VERSION 5.6 ;
BUSBITCHARS "[]" ;
DIVIDERCHAR "/" ;

## M1-M5 covered, ring power

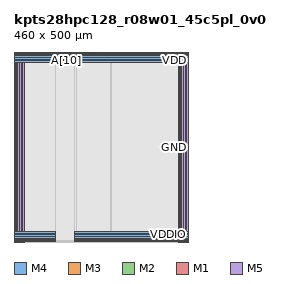
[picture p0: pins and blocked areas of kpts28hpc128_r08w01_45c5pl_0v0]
MACRO kpts28hpc128_r08w01_45c5pl_0v0
  CLASS RING ;
  ORIGIN 0 0 ;
  FOREIGN kpts28hpc128_r08w01_45c5pl_0v0 0 0 ;
  SIZE 460 BY 500 ;
  SYMMETRY X Y ;
  PIN A[0]
    DIRECTION INPUT ;
    USE SIGNAL ;
    ANTENNAPARTIALMETALAREA 0.21865 LAYER M3 ;
    ANTENNAPARTIALMETALAREA 0.0143 LAYER M2 ;
    ANTENNAPARTIALMETALAREA 0.0143 LAYER M4 ;
    ANTENNAPARTIALMETALAREA 0.0143 LAYER M1 ;
    ANTENNAPARTIALCUTAREA 0.005 LAYER VIA3 ;
    ANTENNAPARTIALCUTAREA 0.005 LAYER VIA2 ;
    ANTENNAPARTIALCUTAREA 0.005 LAYER VIA1 ;
    ANTENNAMODEL OXIDE1 ;
      ANTENNAGATEAREA 0.0217 LAYER M3 ;
      ANTENNAGATEAREA 0.0217 LAYER M4 ;
      ANTENNAMAXAREACAR 12.52765 LAYER M3 ;
      ANTENNAMAXAREACAR 13.74424 LAYER M4 ;
      ANTENNAMAXSIDEAREACAR 24.345622 LAYER M3 ;
      ANTENNAMAXSIDEAREACAR 27.248848 LAYER M4 ;
      ANTENNAMAXCUTCAR 0.691244 LAYER VIA3 ;
    PORT
      LAYER M4 ;
        RECT 153.79 499.89 153.9 500 ;
      LAYER M3 ;
        RECT 153.79 499.89 153.9 500 ;
      LAYER M2 ;
        RECT 153.79 499.89 153.9 500 ;
      LAYER M1 ;
        RECT 153.79 499.89 153.9 500 ;
    END
  END A[0]
  PIN A[10]
    DIRECTION INPUT ;
    USE SIGNAL ;
    ANTENNAPARTIALMETALAREA 0.21865 LAYER M3 ;
    ANTENNAPARTIALMETALAREA 0.0143 LAYER M2 ;
    ANTENNAPARTIALMETALAREA 0.0143 LAYER M4 ;
    ANTENNAPARTIALMETALAREA 0.0143 LAYER M1 ;
    ANTENNAPARTIALCUTAREA 0.005 LAYER VIA3 ;
    ANTENNAPARTIALCUTAREA 0.005 LAYER VIA2 ;
    ANTENNAPARTIALCUTAREA 0.005 LAYER VIA1 ;
    ANTENNAMODEL OXIDE1 ;
      ANTENNAGATEAREA 0.0217 LAYER M3 ;
      ANTENNAGATEAREA 0.0217 LAYER M4 ;
      ANTENNAMAXAREACAR 12.52765 LAYER M3 ;
      ANTENNAMAXAREACAR 13.74424 LAYER M4 ;
      ANTENNAMAXSIDEAREACAR 24.345622 LAYER M3 ;
      ANTENNAMAXSIDEAREACAR 27.248848 LAYER M4 ;
      ANTENNAMAXCUTCAR 0.691244 LAYER VIA3 ;
    PORT
      LAYER M4 ;
        RECT 137.59 499.89 137.7 500 ;
      LAYER M3 ;
        RECT 137.59 499.89 137.7 500 ;
      LAYER M2 ;
        RECT 137.59 499.89 137.7 500 ;
      LAYER M1 ;
        RECT 137.59 499.89 137.7 500 ;
    END
  END A[10]
  PIN A[11]
    DIRECTION INPUT ;
    USE SIGNAL ;
    ANTENNAPARTIALMETALAREA 0.21865 LAYER M3 ;
    ANTENNAPARTIALMETALAREA 0.0143 LAYER M2 ;
    ANTENNAPARTIALMETALAREA 0.0143 LAYER M4 ;
    ANTENNAPARTIALMETALAREA 0.0143 LAYER M1 ;
    ANTENNAPARTIALCUTAREA 0.005 LAYER VIA3 ;
    ANTENNAPARTIALCUTAREA 0.005 LAYER VIA2 ;
    ANTENNAPARTIALCUTAREA 0.005 LAYER VIA1 ;
    ANTENNAMODEL OXIDE1 ;
      ANTENNAGATEAREA 0.0217 LAYER M3 ;
      ANTENNAGATEAREA 0.0217 LAYER M4 ;
      ANTENNAMAXAREACAR 12.52765 LAYER M3 ;
      ANTENNAMAXAREACAR 13.74424 LAYER M4 ;
      ANTENNAMAXSIDEAREACAR 24.345622 LAYER M3 ;
      ANTENNAMAXSIDEAREACAR 27.248848 LAYER M4 ;
      ANTENNAMAXCUTCAR 0.691244 LAYER VIA3 ;
    PORT
      LAYER M4 ;
        RECT 135.97 499.89 136.08 500 ;
      LAYER M3 ;
        RECT 135.97 499.89 136.08 500 ;
      LAYER M2 ;
        RECT 135.97 499.89 136.08 500 ;
      LAYER M1 ;
        RECT 135.97 499.89 136.08 500 ;
    END
  END A[11]
  PIN A[12]
    DIRECTION INPUT ;
    USE SIGNAL ;
    ANTENNAPARTIALMETALAREA 0.21865 LAYER M3 ;
    ANTENNAPARTIALMETALAREA 0.0143 LAYER M2 ;
    ANTENNAPARTIALMETALAREA 0.0143 LAYER M4 ;
    ANTENNAPARTIALMETALAREA 0.0143 LAYER M1 ;
    ANTENNAPARTIALCUTAREA 0.005 LAYER VIA3 ;
    ANTENNAPARTIALCUTAREA 0.005 LAYER VIA2 ;
    ANTENNAPARTIALCUTAREA 0.005 LAYER VIA1 ;
    ANTENNAMODEL OXIDE1 ;
      ANTENNAGATEAREA 0.0217 LAYER M3 ;
      ANTENNAGATEAREA 0.0217 LAYER M4 ;
      ANTENNAMAXAREACAR 12.52765 LAYER M3 ;
      ANTENNAMAXAREACAR 13.74424 LAYER M4 ;
      ANTENNAMAXSIDEAREACAR 24.345622 LAYER M3 ;
      ANTENNAMAXSIDEAREACAR 27.248848 LAYER M4 ;
      ANTENNAMAXCUTCAR 0.691244 LAYER VIA3 ;
    PORT
      LAYER M4 ;
        RECT 134.35 499.89 134.46 500 ;
      LAYER M3 ;
        RECT 134.35 499.89 134.46 500 ;
      LAYER M2 ;
        RECT 134.35 499.89 134.46 500 ;
      LAYER M1 ;
        RECT 134.35 499.89 134.46 500 ;
    END
  END A[12]
  PIN A[13]
    DIRECTION INPUT ;
    USE SIGNAL ;
    ANTENNAPARTIALMETALAREA 0.21865 LAYER M3 ;
    ANTENNAPARTIALMETALAREA 0.0143 LAYER M2 ;
    ANTENNAPARTIALMETALAREA 0.0143 LAYER M4 ;
    ANTENNAPARTIALMETALAREA 0.0143 LAYER M1 ;
    ANTENNAPARTIALCUTAREA 0.005 LAYER VIA3 ;
    ANTENNAPARTIALCUTAREA 0.005 LAYER VIA2 ;
    ANTENNAPARTIALCUTAREA 0.005 LAYER VIA1 ;
    ANTENNAMODEL OXIDE1 ;
      ANTENNAGATEAREA 0.0217 LAYER M3 ;
      ANTENNAGATEAREA 0.0217 LAYER M4 ;
      ANTENNAMAXAREACAR 12.52765 LAYER M3 ;
      ANTENNAMAXAREACAR 13.74424 LAYER M4 ;
      ANTENNAMAXSIDEAREACAR 24.345622 LAYER M3 ;
      ANTENNAMAXSIDEAREACAR 27.248848 LAYER M4 ;
      ANTENNAMAXCUTCAR 0.691244 LAYER VIA3 ;
    PORT
      LAYER M4 ;
        RECT 132.73 499.89 132.84 500 ;
      LAYER M3 ;
        RECT 132.73 499.89 132.84 500 ;
      LAYER M2 ;
        RECT 132.73 499.89 132.84 500 ;
      LAYER M1 ;
        RECT 132.73 499.89 132.84 500 ;
    END
  END A[13]
  PIN A[14]
    DIRECTION INPUT ;
    USE SIGNAL ;
    ANTENNAPARTIALMETALAREA 0.21865 LAYER M3 ;
    ANTENNAPARTIALMETALAREA 0.0143 LAYER M2 ;
    ANTENNAPARTIALMETALAREA 0.0143 LAYER M4 ;
    ANTENNAPARTIALMETALAREA 0.0143 LAYER M1 ;
    ANTENNAPARTIALCUTAREA 0.005 LAYER VIA3 ;
    ANTENNAPARTIALCUTAREA 0.005 LAYER VIA2 ;
    ANTENNAPARTIALCUTAREA 0.005 LAYER VIA1 ;
    ANTENNAMODEL OXIDE1 ;
      ANTENNAGATEAREA 0.0217 LAYER M3 ;
      ANTENNAGATEAREA 0.0217 LAYER M4 ;
      ANTENNAMAXAREACAR 12.52765 LAYER M3 ;
      ANTENNAMAXAREACAR 13.74424 LAYER M4 ;
      ANTENNAMAXSIDEAREACAR 24.345622 LAYER M3 ;
      ANTENNAMAXSIDEAREACAR 27.248848 LAYER M4 ;
      ANTENNAMAXCUTCAR 0.691244 LAYER VIA3 ;
    PORT
      LAYER M4 ;
        RECT 131.11 499.89 131.22 500 ;
      LAYER M3 ;
        RECT 131.11 499.89 131.22 500 ;
      LAYER M2 ;
        RECT 131.11 499.89 131.22 500 ;
      LAYER M1 ;
        RECT 131.11 499.89 131.22 500 ;
    END
  END A[14]
  PIN A[15]
    DIRECTION INPUT ;
    USE SIGNAL ;
    ANTENNAPARTIALMETALAREA 0.21865 LAYER M3 ;
    ANTENNAPARTIALMETALAREA 0.0143 LAYER M2 ;
    ANTENNAPARTIALMETALAREA 0.0143 LAYER M4 ;
    ANTENNAPARTIALMETALAREA 0.0143 LAYER M1 ;
    ANTENNAPARTIALCUTAREA 0.005 LAYER VIA3 ;
    ANTENNAPARTIALCUTAREA 0.005 LAYER VIA2 ;
    ANTENNAPARTIALCUTAREA 0.005 LAYER VIA1 ;
    ANTENNAMODEL OXIDE1 ;
      ANTENNAGATEAREA 0.0217 LAYER M3 ;
      ANTENNAGATEAREA 0.0217 LAYER M4 ;
      ANTENNAMAXAREACAR 12.52765 LAYER M3 ;
      ANTENNAMAXAREACAR 13.74424 LAYER M4 ;
      ANTENNAMAXSIDEAREACAR 24.345622 LAYER M3 ;
      ANTENNAMAXSIDEAREACAR 27.248848 LAYER M4 ;
      ANTENNAMAXCUTCAR 0.691244 LAYER VIA3 ;
    PORT
      LAYER M4 ;
        RECT 129.49 499.89 129.6 500 ;
      LAYER M3 ;
        RECT 129.49 499.89 129.6 500 ;
      LAYER M2 ;
        RECT 129.49 499.89 129.6 500 ;
      LAYER M1 ;
        RECT 129.49 499.89 129.6 500 ;
    END
  END A[15]
  PIN A[16]
    DIRECTION INPUT ;
    USE SIGNAL ;
    ANTENNAPARTIALMETALAREA 0.21865 LAYER M3 ;
    ANTENNAPARTIALMETALAREA 0.0143 LAYER M2 ;
    ANTENNAPARTIALMETALAREA 0.0143 LAYER M4 ;
    ANTENNAPARTIALMETALAREA 0.0143 LAYER M1 ;
    ANTENNAPARTIALCUTAREA 0.005 LAYER VIA3 ;
    ANTENNAPARTIALCUTAREA 0.005 LAYER VIA2 ;
    ANTENNAPARTIALCUTAREA 0.005 LAYER VIA1 ;
    ANTENNAMODEL OXIDE1 ;
      ANTENNAGATEAREA 0.0217 LAYER M3 ;
      ANTENNAGATEAREA 0.0217 LAYER M4 ;
      ANTENNAMAXAREACAR 12.52765 LAYER M3 ;
      ANTENNAMAXAREACAR 13.74424 LAYER M4 ;
      ANTENNAMAXSIDEAREACAR 24.345622 LAYER M3 ;
      ANTENNAMAXSIDEAREACAR 27.248848 LAYER M4 ;
      ANTENNAMAXCUTCAR 0.691244 LAYER VIA3 ;
    PORT
      LAYER M4 ;
        RECT 127.87 499.89 127.98 500 ;
      LAYER M3 ;
        RECT 127.87 499.89 127.98 500 ;
      LAYER M2 ;
        RECT 127.87 499.89 127.98 500 ;
      LAYER M1 ;
        RECT 127.87 499.89 127.98 500 ;
    END
  END A[16]
  PIN A[1]
    DIRECTION INPUT ;
    USE SIGNAL ;
    ANTENNAPARTIALMETALAREA 0.21865 LAYER M3 ;
    ANTENNAPARTIALMETALAREA 0.0143 LAYER M2 ;
    ANTENNAPARTIALMETALAREA 0.0143 LAYER M4 ;
    ANTENNAPARTIALMETALAREA 0.0143 LAYER M1 ;
    ANTENNAPARTIALCUTAREA 0.005 LAYER VIA3 ;
    ANTENNAPARTIALCUTAREA 0.005 LAYER VIA2 ;
    ANTENNAPARTIALCUTAREA 0.005 LAYER VIA1 ;
    ANTENNAMODEL OXIDE1 ;
      ANTENNAGATEAREA 0.0217 LAYER M3 ;
      ANTENNAGATEAREA 0.0217 LAYER M4 ;
      ANTENNAMAXAREACAR 12.52765 LAYER M3 ;
      ANTENNAMAXAREACAR 13.74424 LAYER M4 ;
      ANTENNAMAXSIDEAREACAR 24.345622 LAYER M3 ;
      ANTENNAMAXSIDEAREACAR 27.248848 LAYER M4 ;
      ANTENNAMAXCUTCAR 0.691244 LAYER VIA3 ;
    PORT
      LAYER M4 ;
        RECT 152.17 499.89 152.28 500 ;
      LAYER M3 ;
        RECT 152.17 499.89 152.28 500 ;
      LAYER M2 ;
        RECT 152.17 499.89 152.28 500 ;
      LAYER M1 ;
        RECT 152.17 499.89 152.28 500 ;
    END
  END A[1]
  PIN A[2]
    DIRECTION INPUT ;
    USE SIGNAL ;
    ANTENNAPARTIALMETALAREA 0.21865 LAYER M3 ;
    ANTENNAPARTIALMETALAREA 0.0143 LAYER M2 ;
    ANTENNAPARTIALMETALAREA 0.0143 LAYER M4 ;
    ANTENNAPARTIALMETALAREA 0.0143 LAYER M1 ;
    ANTENNAPARTIALCUTAREA 0.005 LAYER VIA3 ;
    ANTENNAPARTIALCUTAREA 0.005 LAYER VIA2 ;
    ANTENNAPARTIALCUTAREA 0.005 LAYER VIA1 ;
    ANTENNAMODEL OXIDE1 ;
      ANTENNAGATEAREA 0.0217 LAYER M3 ;
      ANTENNAGATEAREA 0.0217 LAYER M4 ;
      ANTENNAMAXAREACAR 12.52765 LAYER M3 ;
      ANTENNAMAXAREACAR 13.74424 LAYER M4 ;
      ANTENNAMAXSIDEAREACAR 24.345622 LAYER M3 ;
      ANTENNAMAXSIDEAREACAR 27.248848 LAYER M4 ;
      ANTENNAMAXCUTCAR 0.691244 LAYER VIA3 ;
    PORT
      LAYER M4 ;
        RECT 150.55 499.89 150.66 500 ;
      LAYER M3 ;
        RECT 150.55 499.89 150.66 500 ;
      LAYER M2 ;
        RECT 150.55 499.89 150.66 500 ;
      LAYER M1 ;
        RECT 150.55 499.89 150.66 500 ;
    END
  END A[2]
  PIN A[3]
    DIRECTION INPUT ;
    USE SIGNAL ;
    ANTENNAPARTIALMETALAREA 0.21865 LAYER M3 ;
    ANTENNAPARTIALMETALAREA 0.0143 LAYER M2 ;
    ANTENNAPARTIALMETALAREA 0.0143 LAYER M4 ;
    ANTENNAPARTIALMETALAREA 0.0143 LAYER M1 ;
    ANTENNAPARTIALCUTAREA 0.005 LAYER VIA3 ;
    ANTENNAPARTIALCUTAREA 0.005 LAYER VIA2 ;
    ANTENNAPARTIALCUTAREA 0.005 LAYER VIA1 ;
    ANTENNAMODEL OXIDE1 ;
      ANTENNAGATEAREA 0.0217 LAYER M3 ;
      ANTENNAGATEAREA 0.0217 LAYER M4 ;
      ANTENNAMAXAREACAR 12.52765 LAYER M3 ;
      ANTENNAMAXAREACAR 13.74424 LAYER M4 ;
      ANTENNAMAXSIDEAREACAR 24.345622 LAYER M3 ;
      ANTENNAMAXSIDEAREACAR 27.248848 LAYER M4 ;
      ANTENNAMAXCUTCAR 0.691244 LAYER VIA3 ;
    PORT
      LAYER M4 ;
        RECT 148.93 499.89 149.04 500 ;
      LAYER M3 ;
        RECT 148.93 499.89 149.04 500 ;
      LAYER M2 ;
        RECT 148.93 499.89 149.04 500 ;
      LAYER M1 ;
        RECT 148.93 499.89 149.04 500 ;
    END
  END A[3]
  PIN A[4]
    DIRECTION INPUT ;
    USE SIGNAL ;
    ANTENNAPARTIALMETALAREA 0.21865 LAYER M3 ;
    ANTENNAPARTIALMETALAREA 0.0143 LAYER M2 ;
    ANTENNAPARTIALMETALAREA 0.0143 LAYER M4 ;
    ANTENNAPARTIALMETALAREA 0.0143 LAYER M1 ;
    ANTENNAPARTIALCUTAREA 0.005 LAYER VIA3 ;
    ANTENNAPARTIALCUTAREA 0.005 LAYER VIA2 ;
    ANTENNAPARTIALCUTAREA 0.005 LAYER VIA1 ;
    ANTENNAMODEL OXIDE1 ;
      ANTENNAGATEAREA 0.0217 LAYER M3 ;
      ANTENNAGATEAREA 0.0217 LAYER M4 ;
      ANTENNAMAXAREACAR 12.52765 LAYER M3 ;
      ANTENNAMAXAREACAR 13.74424 LAYER M4 ;
      ANTENNAMAXSIDEAREACAR 24.345622 LAYER M3 ;
      ANTENNAMAXSIDEAREACAR 27.248848 LAYER M4 ;
      ANTENNAMAXCUTCAR 0.691244 LAYER VIA3 ;
    PORT
      LAYER M4 ;
        RECT 147.31 499.89 147.42 500 ;
      LAYER M3 ;
        RECT 147.31 499.89 147.42 500 ;
      LAYER M2 ;
        RECT 147.31 499.89 147.42 500 ;
      LAYER M1 ;
        RECT 147.31 499.89 147.42 500 ;
    END
  END A[4]
  PIN A[5]
    DIRECTION INPUT ;
    USE SIGNAL ;
    ANTENNAPARTIALMETALAREA 0.21865 LAYER M3 ;
    ANTENNAPARTIALMETALAREA 0.0143 LAYER M2 ;
    ANTENNAPARTIALMETALAREA 0.0143 LAYER M4 ;
    ANTENNAPARTIALMETALAREA 0.0143 LAYER M1 ;
    ANTENNAPARTIALCUTAREA 0.005 LAYER VIA3 ;
    ANTENNAPARTIALCUTAREA 0.005 LAYER VIA2 ;
    ANTENNAPARTIALCUTAREA 0.005 LAYER VIA1 ;
    ANTENNAMODEL OXIDE1 ;
      ANTENNAGATEAREA 0.0217 LAYER M3 ;
      ANTENNAGATEAREA 0.0217 LAYER M4 ;
      ANTENNAMAXAREACAR 12.52765 LAYER M3 ;
      ANTENNAMAXAREACAR 13.74424 LAYER M4 ;
      ANTENNAMAXSIDEAREACAR 24.345622 LAYER M3 ;
      ANTENNAMAXSIDEAREACAR 27.248848 LAYER M4 ;
      ANTENNAMAXCUTCAR 0.691244 LAYER VIA3 ;
    PORT
      LAYER M4 ;
        RECT 145.69 499.89 145.8 500 ;
      LAYER M3 ;
        RECT 145.69 499.89 145.8 500 ;
      LAYER M2 ;
        RECT 145.69 499.89 145.8 500 ;
      LAYER M1 ;
        RECT 145.69 499.89 145.8 500 ;
    END
  END A[5]
  PIN A[6]
    DIRECTION INPUT ;
    USE SIGNAL ;
    ANTENNAPARTIALMETALAREA 0.21865 LAYER M3 ;
    ANTENNAPARTIALMETALAREA 0.0143 LAYER M2 ;
    ANTENNAPARTIALMETALAREA 0.0143 LAYER M4 ;
    ANTENNAPARTIALMETALAREA 0.0143 LAYER M1 ;
    ANTENNAPARTIALCUTAREA 0.005 LAYER VIA3 ;
    ANTENNAPARTIALCUTAREA 0.005 LAYER VIA2 ;
    ANTENNAPARTIALCUTAREA 0.005 LAYER VIA1 ;
    ANTENNAMODEL OXIDE1 ;
      ANTENNAGATEAREA 0.0217 LAYER M3 ;
      ANTENNAGATEAREA 0.0217 LAYER M4 ;
      ANTENNAMAXAREACAR 12.52765 LAYER M3 ;
      ANTENNAMAXAREACAR 13.74424 LAYER M4 ;
      ANTENNAMAXSIDEAREACAR 24.345622 LAYER M3 ;
      ANTENNAMAXSIDEAREACAR 27.248848 LAYER M4 ;
      ANTENNAMAXCUTCAR 0.691244 LAYER VIA3 ;
    PORT
      LAYER M4 ;
        RECT 144.07 499.89 144.18 500 ;
      LAYER M3 ;
        RECT 144.07 499.89 144.18 500 ;
      LAYER M2 ;
        RECT 144.07 499.89 144.18 500 ;
      LAYER M1 ;
        RECT 144.07 499.89 144.18 500 ;
    END
  END A[6]
  PIN A[7]
    DIRECTION INPUT ;
    USE SIGNAL ;
    ANTENNAPARTIALMETALAREA 0.21865 LAYER M3 ;
    ANTENNAPARTIALMETALAREA 0.0143 LAYER M2 ;
    ANTENNAPARTIALMETALAREA 0.0143 LAYER M4 ;
    ANTENNAPARTIALMETALAREA 0.0143 LAYER M1 ;
    ANTENNAPARTIALCUTAREA 0.005 LAYER VIA3 ;
    ANTENNAPARTIALCUTAREA 0.005 LAYER VIA2 ;
    ANTENNAPARTIALCUTAREA 0.005 LAYER VIA1 ;
    ANTENNAMODEL OXIDE1 ;
      ANTENNAGATEAREA 0.0217 LAYER M3 ;
      ANTENNAGATEAREA 0.0217 LAYER M4 ;
      ANTENNAMAXAREACAR 12.52765 LAYER M3 ;
      ANTENNAMAXAREACAR 13.74424 LAYER M4 ;
      ANTENNAMAXSIDEAREACAR 24.345622 LAYER M3 ;
      ANTENNAMAXSIDEAREACAR 27.248848 LAYER M4 ;
      ANTENNAMAXCUTCAR 0.691244 LAYER VIA3 ;
    PORT
      LAYER M4 ;
        RECT 142.45 499.89 142.56 500 ;
      LAYER M3 ;
        RECT 142.45 499.89 142.56 500 ;
      LAYER M2 ;
        RECT 142.45 499.89 142.56 500 ;
      LAYER M1 ;
        RECT 142.45 499.89 142.56 500 ;
    END
  END A[7]
  PIN A[8]
    DIRECTION INPUT ;
    USE SIGNAL ;
    ANTENNAPARTIALMETALAREA 0.21865 LAYER M3 ;
    ANTENNAPARTIALMETALAREA 0.0143 LAYER M2 ;
    ANTENNAPARTIALMETALAREA 0.0143 LAYER M4 ;
    ANTENNAPARTIALMETALAREA 0.0143 LAYER M1 ;
    ANTENNAPARTIALCUTAREA 0.005 LAYER VIA3 ;
    ANTENNAPARTIALCUTAREA 0.005 LAYER VIA2 ;
    ANTENNAPARTIALCUTAREA 0.005 LAYER VIA1 ;
    ANTENNAMODEL OXIDE1 ;
      ANTENNAGATEAREA 0.0217 LAYER M3 ;
      ANTENNAGATEAREA 0.0217 LAYER M4 ;
      ANTENNAMAXAREACAR 12.52765 LAYER M3 ;
      ANTENNAMAXAREACAR 13.74424 LAYER M4 ;
      ANTENNAMAXSIDEAREACAR 24.345622 LAYER M3 ;
      ANTENNAMAXSIDEAREACAR 27.248848 LAYER M4 ;
      ANTENNAMAXCUTCAR 0.691244 LAYER VIA3 ;
    PORT
      LAYER M4 ;
        RECT 140.83 499.89 140.94 500 ;
      LAYER M3 ;
        RECT 140.83 499.89 140.94 500 ;
      LAYER M2 ;
        RECT 140.83 499.89 140.94 500 ;
      LAYER M1 ;
        RECT 140.83 499.89 140.94 500 ;
    END
  END A[8]
  PIN A[9]
    DIRECTION INPUT ;
    USE SIGNAL ;
    ANTENNAPARTIALMETALAREA 0.21865 LAYER M3 ;
    ANTENNAPARTIALMETALAREA 0.0143 LAYER M2 ;
    ANTENNAPARTIALMETALAREA 0.0143 LAYER M4 ;
    ANTENNAPARTIALMETALAREA 0.0143 LAYER M1 ;
    ANTENNAPARTIALCUTAREA 0.005 LAYER VIA3 ;
    ANTENNAPARTIALCUTAREA 0.005 LAYER VIA2 ;
    ANTENNAPARTIALCUTAREA 0.005 LAYER VIA1 ;
    ANTENNAMODEL OXIDE1 ;
      ANTENNAGATEAREA 0.0217 LAYER M3 ;
      ANTENNAGATEAREA 0.0217 LAYER M4 ;
      ANTENNAMAXAREACAR 12.52765 LAYER M3 ;
      ANTENNAMAXAREACAR 13.74424 LAYER M4 ;
      ANTENNAMAXSIDEAREACAR 24.345622 LAYER M3 ;
      ANTENNAMAXSIDEAREACAR 27.248848 LAYER M4 ;
      ANTENNAMAXCUTCAR 0.691244 LAYER VIA3 ;
    PORT
      LAYER M4 ;
        RECT 139.21 499.89 139.32 500 ;
      LAYER M3 ;
        RECT 139.21 499.89 139.32 500 ;
      LAYER M2 ;
        RECT 139.21 499.89 139.32 500 ;
      LAYER M1 ;
        RECT 139.21 499.89 139.32 500 ;
    END
  END A[9]
  PIN CEB
    DIRECTION INPUT ;
    USE SIGNAL ;
    ANTENNAPARTIALMETALAREA 0.20325 LAYER M3 ;
    ANTENNAPARTIALMETALAREA 0.0143 LAYER M2 ;
    ANTENNAPARTIALMETALAREA 0.0143 LAYER M4 ;
    ANTENNAPARTIALMETALAREA 0.0143 LAYER M1 ;
    ANTENNAPARTIALCUTAREA 0.005 LAYER VIA3 ;
    ANTENNAPARTIALCUTAREA 0.005 LAYER VIA2 ;
    ANTENNAPARTIALCUTAREA 0.005 LAYER VIA1 ;
    ANTENNAMODEL OXIDE1 ;
      ANTENNAGATEAREA 0.0217 LAYER M3 ;
      ANTENNAGATEAREA 0.0217 LAYER M4 ;
      ANTENNAMAXAREACAR 10.914747 LAYER M3 ;
      ANTENNAMAXAREACAR 12.131336 LAYER M4 ;
      ANTENNAMAXSIDEAREACAR 20.861751 LAYER M3 ;
      ANTENNAMAXSIDEAREACAR 23.764977 LAYER M4 ;
      ANTENNAMAXCUTCAR 0.691244 LAYER VIA3 ;
    PORT
      LAYER M4 ;
        RECT 155.325 499.89 155.435 500 ;
      LAYER M3 ;
        RECT 155.325 499.89 155.435 500 ;
      LAYER M2 ;
        RECT 155.325 499.89 155.435 500 ;
      LAYER M1 ;
        RECT 155.325 499.89 155.435 500 ;
    END
  END CEB
  PIN CLE
    DIRECTION INPUT ;
    USE SIGNAL ;
    ANTENNAPARTIALMETALAREA 0.21865 LAYER M3 ;
    ANTENNAPARTIALMETALAREA 0.0143 LAYER M2 ;
    ANTENNAPARTIALMETALAREA 0.0143 LAYER M4 ;
    ANTENNAPARTIALMETALAREA 0.0143 LAYER M1 ;
    ANTENNAPARTIALCUTAREA 0.005 LAYER VIA3 ;
    ANTENNAPARTIALCUTAREA 0.005 LAYER VIA2 ;
    ANTENNAPARTIALCUTAREA 0.005 LAYER VIA1 ;
    ANTENNAMODEL OXIDE1 ;
      ANTENNAGATEAREA 0.0217 LAYER M3 ;
      ANTENNAGATEAREA 0.0217 LAYER M4 ;
      ANTENNAMAXAREACAR 12.52765 LAYER M3 ;
      ANTENNAMAXAREACAR 13.74424 LAYER M4 ;
      ANTENNAMAXSIDEAREACAR 24.345622 LAYER M3 ;
      ANTENNAMAXSIDEAREACAR 27.248848 LAYER M4 ;
      ANTENNAMAXCUTCAR 0.691244 LAYER VIA3 ;
    PORT
      LAYER M4 ;
        RECT 113.965 499.89 114.075 500 ;
      LAYER M3 ;
        RECT 113.965 499.89 114.075 500 ;
      LAYER M2 ;
        RECT 113.965 499.89 114.075 500 ;
      LAYER M1 ;
        RECT 113.965 499.89 114.075 500 ;
    END
  END CLE
  PIN CPUMPEN
    DIRECTION INPUT ;
    USE SIGNAL ;
    ANTENNAPARTIALMETALAREA 0.21865 LAYER M3 ;
    ANTENNAPARTIALMETALAREA 0.0143 LAYER M2 ;
    ANTENNAPARTIALMETALAREA 0.0143 LAYER M4 ;
    ANTENNAPARTIALMETALAREA 0.0143 LAYER M1 ;
    ANTENNAPARTIALCUTAREA 0.005 LAYER VIA3 ;
    ANTENNAPARTIALCUTAREA 0.005 LAYER VIA2 ;
    ANTENNAPARTIALCUTAREA 0.005 LAYER VIA1 ;
    ANTENNAMODEL OXIDE1 ;
      ANTENNAGATEAREA 0.0217 LAYER M3 ;
      ANTENNAGATEAREA 0.0217 LAYER M4 ;
      ANTENNAMAXAREACAR 12.52765 LAYER M3 ;
      ANTENNAMAXAREACAR 13.74424 LAYER M4 ;
      ANTENNAMAXSIDEAREACAR 24.345622 LAYER M3 ;
      ANTENNAMAXSIDEAREACAR 27.248848 LAYER M4 ;
      ANTENNAMAXCUTCAR 0.691244 LAYER VIA3 ;
    PORT
      LAYER M4 ;
        RECT 116.665 499.89 116.775 500 ;
      LAYER M3 ;
        RECT 116.665 499.89 116.775 500 ;
      LAYER M2 ;
        RECT 116.665 499.89 116.775 500 ;
      LAYER M1 ;
        RECT 116.665 499.89 116.775 500 ;
    END
  END CPUMPEN
  PIN DIN
    DIRECTION INPUT ;
    USE SIGNAL ;
    ANTENNAPARTIALMETALAREA 0.20955 LAYER M3 ;
    ANTENNAPARTIALMETALAREA 0.0143 LAYER M2 ;
    ANTENNAPARTIALMETALAREA 0.0143 LAYER M4 ;
    ANTENNAPARTIALMETALAREA 0.0143 LAYER M1 ;
    ANTENNAPARTIALCUTAREA 0.005 LAYER VIA3 ;
    ANTENNAPARTIALCUTAREA 0.005 LAYER VIA2 ;
    ANTENNAPARTIALCUTAREA 0.005 LAYER VIA1 ;
    ANTENNAMODEL OXIDE1 ;
      ANTENNAGATEAREA 0.0217 LAYER M3 ;
      ANTENNAGATEAREA 0.0217 LAYER M4 ;
      ANTENNAMAXAREACAR 11.085253 LAYER M3 ;
      ANTENNAMAXAREACAR 12.301843 LAYER M4 ;
      ANTENNAMAXSIDEAREACAR 21.774194 LAYER M3 ;
      ANTENNAMAXSIDEAREACAR 24.677419 LAYER M4 ;
      ANTENNAMAXCUTCAR 0.691244 LAYER VIA3 ;
    PORT
      LAYER M4 ;
        RECT 161.965 499.89 162.075 500 ;
      LAYER M3 ;
        RECT 161.965 499.89 162.075 500 ;
      LAYER M2 ;
        RECT 161.965 499.89 162.075 500 ;
      LAYER M1 ;
        RECT 161.965 499.89 162.075 500 ;
    END
  END DIN
  PIN DLE
    DIRECTION INPUT ;
    USE SIGNAL ;
    ANTENNAPARTIALMETALAREA 0.21865 LAYER M3 ;
    ANTENNAPARTIALMETALAREA 0.0143 LAYER M2 ;
    ANTENNAPARTIALMETALAREA 0.0143 LAYER M4 ;
    ANTENNAPARTIALMETALAREA 0.0143 LAYER M1 ;
    ANTENNAPARTIALCUTAREA 0.005 LAYER VIA3 ;
    ANTENNAPARTIALCUTAREA 0.005 LAYER VIA2 ;
    ANTENNAPARTIALCUTAREA 0.005 LAYER VIA1 ;
    ANTENNAMODEL OXIDE1 ;
      ANTENNAGATEAREA 0.0217 LAYER M3 ;
      ANTENNAGATEAREA 0.0217 LAYER M4 ;
      ANTENNAMAXAREACAR 12.52765 LAYER M3 ;
      ANTENNAMAXAREACAR 13.74424 LAYER M4 ;
      ANTENNAMAXSIDEAREACAR 24.345622 LAYER M3 ;
      ANTENNAMAXSIDEAREACAR 27.248848 LAYER M4 ;
      ANTENNAMAXCUTCAR 0.691244 LAYER VIA3 ;
    PORT
      LAYER M4 ;
        RECT 115.315 499.89 115.425 500 ;
      LAYER M3 ;
        RECT 115.315 499.89 115.425 500 ;
      LAYER M2 ;
        RECT 115.315 499.89 115.425 500 ;
      LAYER M1 ;
        RECT 115.315 499.89 115.425 500 ;
    END
  END DLE
  PIN D[0]
    DIRECTION OUTPUT ;
    USE SIGNAL ;
    ANTENNAPARTIALMETALAREA 9.196 LAYER M3 ;
    ANTENNAPARTIALMETALAREA 0.0143 LAYER M2 ;
    ANTENNAPARTIALMETALAREA 2.9073 LAYER M4 ;
    ANTENNAPARTIALMETALAREA 0.0143 LAYER M1 ;
    ANTENNAPARTIALCUTAREA 0.01 LAYER VIA3 ;
    ANTENNAPARTIALCUTAREA 0.005 LAYER VIA2 ;
    ANTENNAPARTIALCUTAREA 0.005 LAYER VIA1 ;
    PORT
      LAYER M4 ;
        RECT 170.445 499.89 170.555 500 ;
      LAYER M3 ;
        RECT 170.445 499.89 170.555 500 ;
      LAYER M2 ;
        RECT 170.445 499.89 170.555 500 ;
      LAYER M1 ;
        RECT 170.445 499.89 170.555 500 ;
    END
  END D[0]
  PIN D[1]
    DIRECTION OUTPUT ;
    USE SIGNAL ;
    ANTENNAPARTIALMETALAREA 9.2202 LAYER M3 ;
    ANTENNAPARTIALMETALAREA 0.0143 LAYER M2 ;
    ANTENNAPARTIALMETALAREA 2.9073 LAYER M4 ;
    ANTENNAPARTIALMETALAREA 0.0143 LAYER M1 ;
    ANTENNAPARTIALCUTAREA 0.01 LAYER VIA3 ;
    ANTENNAPARTIALCUTAREA 0.005 LAYER VIA2 ;
    ANTENNAPARTIALCUTAREA 0.005 LAYER VIA1 ;
    PORT
      LAYER M4 ;
        RECT 172.055 499.89 172.165 500 ;
      LAYER M3 ;
        RECT 172.055 499.89 172.165 500 ;
      LAYER M2 ;
        RECT 172.055 499.89 172.165 500 ;
      LAYER M1 ;
        RECT 172.055 499.89 172.165 500 ;
    END
  END D[1]
  PIN D[2]
    DIRECTION OUTPUT ;
    USE SIGNAL ;
    ANTENNAPARTIALMETALAREA 9.2543 LAYER M3 ;
    ANTENNAPARTIALMETALAREA 0.0143 LAYER M2 ;
    ANTENNAPARTIALMETALAREA 2.8622 LAYER M4 ;
    ANTENNAPARTIALMETALAREA 0.0143 LAYER M1 ;
    ANTENNAPARTIALCUTAREA 0.01 LAYER VIA3 ;
    ANTENNAPARTIALCUTAREA 0.005 LAYER VIA2 ;
    ANTENNAPARTIALCUTAREA 0.005 LAYER VIA1 ;
    PORT
      LAYER M4 ;
        RECT 173.665 499.89 173.775 500 ;
      LAYER M3 ;
        RECT 173.665 499.89 173.775 500 ;
      LAYER M2 ;
        RECT 173.665 499.89 173.775 500 ;
      LAYER M1 ;
        RECT 173.665 499.89 173.775 500 ;
    END
  END D[2]
  PIN D[3]
    DIRECTION OUTPUT ;
    USE SIGNAL ;
    ANTENNAPARTIALMETALAREA 9.1487 LAYER M3 ;
    ANTENNAPARTIALMETALAREA 0.3234 LAYER M2 ;
    ANTENNAPARTIALMETALAREA 2.8622 LAYER M4 ;
    ANTENNAPARTIALMETALAREA 0.0143 LAYER M1 ;
    ANTENNAPARTIALCUTAREA 0.01 LAYER VIA3 ;
    ANTENNAPARTIALCUTAREA 0.01 LAYER VIA2 ;
    ANTENNAPARTIALCUTAREA 0.005 LAYER VIA1 ;
    PORT
      LAYER M4 ;
        RECT 175.275 499.89 175.385 500 ;
      LAYER M3 ;
        RECT 175.275 499.89 175.385 500 ;
      LAYER M2 ;
        RECT 175.275 499.89 175.385 500 ;
      LAYER M1 ;
        RECT 175.275 499.89 175.385 500 ;
    END
  END D[3]
  PIN D[4]
    DIRECTION OUTPUT ;
    USE SIGNAL ;
    ANTENNAPARTIALMETALAREA 9.1487 LAYER M3 ;
    ANTENNAPARTIALMETALAREA 0.5005 LAYER M2 ;
    ANTENNAPARTIALMETALAREA 2.69885 LAYER M4 ;
    ANTENNAPARTIALMETALAREA 0.0143 LAYER M1 ;
    ANTENNAPARTIALCUTAREA 0.01 LAYER VIA3 ;
    ANTENNAPARTIALCUTAREA 0.01 LAYER VIA2 ;
    ANTENNAPARTIALCUTAREA 0.005 LAYER VIA1 ;
    PORT
      LAYER M4 ;
        RECT 176.885 499.89 176.995 500 ;
      LAYER M3 ;
        RECT 176.885 499.89 176.995 500 ;
      LAYER M2 ;
        RECT 176.885 499.89 176.995 500 ;
      LAYER M1 ;
        RECT 176.885 499.89 176.995 500 ;
    END
  END D[4]
  PIN D[5]
    DIRECTION OUTPUT ;
    USE SIGNAL ;
    ANTENNAPARTIALMETALAREA 9.1487 LAYER M3 ;
    ANTENNAPARTIALMETALAREA 0.6776 LAYER M2 ;
    ANTENNAPARTIALMETALAREA 2.69885 LAYER M4 ;
    ANTENNAPARTIALMETALAREA 0.0143 LAYER M1 ;
    ANTENNAPARTIALCUTAREA 0.01 LAYER VIA3 ;
    ANTENNAPARTIALCUTAREA 0.01 LAYER VIA2 ;
    ANTENNAPARTIALCUTAREA 0.005 LAYER VIA1 ;
    PORT
      LAYER M4 ;
        RECT 178.495 499.89 178.605 500 ;
      LAYER M3 ;
        RECT 178.495 499.89 178.605 500 ;
      LAYER M2 ;
        RECT 178.495 499.89 178.605 500 ;
      LAYER M1 ;
        RECT 178.495 499.89 178.605 500 ;
    END
  END D[5]
  PIN D[6]
    DIRECTION OUTPUT ;
    USE SIGNAL ;
    ANTENNAPARTIALMETALAREA 9.3555 LAYER M3 ;
    ANTENNAPARTIALMETALAREA 0.0143 LAYER M2 ;
    ANTENNAPARTIALMETALAREA 2.6983 LAYER M4 ;
    ANTENNAPARTIALMETALAREA 0.0143 LAYER M1 ;
    ANTENNAPARTIALCUTAREA 0.01 LAYER VIA3 ;
    ANTENNAPARTIALCUTAREA 0.005 LAYER VIA2 ;
    ANTENNAPARTIALCUTAREA 0.005 LAYER VIA1 ;
    PORT
      LAYER M4 ;
        RECT 180.105 499.89 180.215 500 ;
      LAYER M3 ;
        RECT 180.105 499.89 180.215 500 ;
      LAYER M2 ;
        RECT 180.105 499.89 180.215 500 ;
      LAYER M1 ;
        RECT 180.105 499.89 180.215 500 ;
    END
  END D[6]
  PIN D[7]
    DIRECTION OUTPUT ;
    USE SIGNAL ;
    ANTENNAPARTIALMETALAREA 9.3797 LAYER M3 ;
    ANTENNAPARTIALMETALAREA 0.0143 LAYER M2 ;
    ANTENNAPARTIALMETALAREA 2.6983 LAYER M4 ;
    ANTENNAPARTIALMETALAREA 0.0143 LAYER M1 ;
    ANTENNAPARTIALCUTAREA 0.01 LAYER VIA3 ;
    ANTENNAPARTIALCUTAREA 0.005 LAYER VIA2 ;
    ANTENNAPARTIALCUTAREA 0.005 LAYER VIA1 ;
    PORT
      LAYER M4 ;
        RECT 181.715 499.89 181.825 500 ;
      LAYER M3 ;
        RECT 181.715 499.89 181.825 500 ;
      LAYER M2 ;
        RECT 181.715 499.89 181.825 500 ;
      LAYER M1 ;
        RECT 181.715 499.89 181.825 500 ;
    END
  END D[7]
  PIN LOCK
    DIRECTION OUTPUT ;
    USE SIGNAL ;
    ANTENNAPARTIALMETALAREA 9.80225 LAYER M3 ;
    ANTENNAPARTIALMETALAREA 0.0143 LAYER M2 ;
    ANTENNAPARTIALMETALAREA 0.0143 LAYER M4 ;
    ANTENNAPARTIALMETALAREA 0.0143 LAYER M1 ;
    ANTENNAPARTIALCUTAREA 0.005 LAYER VIA3 ;
    ANTENNAPARTIALCUTAREA 0.005 LAYER VIA2 ;
    ANTENNAPARTIALCUTAREA 0.005 LAYER VIA1 ;
    PORT
      LAYER M4 ;
        RECT 123.345 499.89 123.455 500 ;
      LAYER M3 ;
        RECT 123.345 499.89 123.455 500 ;
      LAYER M2 ;
        RECT 123.345 499.89 123.455 500 ;
      LAYER M1 ;
        RECT 123.345 499.89 123.455 500 ;
    END
  END LOCK
  PIN PGMEN
    DIRECTION INPUT ;
    USE SIGNAL ;
    ANTENNAPARTIALMETALAREA 0.21865 LAYER M3 ;
    ANTENNAPARTIALMETALAREA 0.0143 LAYER M2 ;
    ANTENNAPARTIALMETALAREA 0.0143 LAYER M4 ;
    ANTENNAPARTIALMETALAREA 0.0143 LAYER M1 ;
    ANTENNAPARTIALCUTAREA 0.005 LAYER VIA3 ;
    ANTENNAPARTIALCUTAREA 0.005 LAYER VIA2 ;
    ANTENNAPARTIALCUTAREA 0.005 LAYER VIA1 ;
    ANTENNAMODEL OXIDE1 ;
      ANTENNAGATEAREA 0.0217 LAYER M3 ;
      ANTENNAGATEAREA 0.0217 LAYER M4 ;
      ANTENNAMAXAREACAR 12.52765 LAYER M3 ;
      ANTENNAMAXAREACAR 13.74424 LAYER M4 ;
      ANTENNAMAXSIDEAREACAR 24.345622 LAYER M3 ;
      ANTENNAMAXSIDEAREACAR 27.248848 LAYER M4 ;
      ANTENNAMAXCUTCAR 0.691244 LAYER VIA3 ;
    PORT
      LAYER M4 ;
        RECT 119.905 499.89 120.015 500 ;
      LAYER M3 ;
        RECT 119.905 499.89 120.015 500 ;
      LAYER M2 ;
        RECT 119.905 499.89 120.015 500 ;
      LAYER M1 ;
        RECT 119.905 499.89 120.015 500 ;
    END
  END PGMEN
  PIN READEN
    DIRECTION INPUT ;
    USE SIGNAL ;
    ANTENNAPARTIALMETALAREA 0.21865 LAYER M3 ;
    ANTENNAPARTIALMETALAREA 0.0143 LAYER M2 ;
    ANTENNAPARTIALMETALAREA 0.0143 LAYER M4 ;
    ANTENNAPARTIALMETALAREA 0.0143 LAYER M1 ;
    ANTENNAPARTIALCUTAREA 0.005 LAYER VIA3 ;
    ANTENNAPARTIALCUTAREA 0.005 LAYER VIA2 ;
    ANTENNAPARTIALCUTAREA 0.005 LAYER VIA1 ;
    ANTENNAMODEL OXIDE1 ;
      ANTENNAGATEAREA 0.0217 LAYER M3 ;
      ANTENNAGATEAREA 0.0217 LAYER M4 ;
      ANTENNAMAXAREACAR 12.52765 LAYER M3 ;
      ANTENNAMAXAREACAR 13.74424 LAYER M4 ;
      ANTENNAMAXSIDEAREACAR 24.345622 LAYER M3 ;
      ANTENNAMAXSIDEAREACAR 27.248848 LAYER M4 ;
      ANTENNAMAXCUTCAR 0.691244 LAYER VIA3 ;
    PORT
      LAYER M4 ;
        RECT 124.63 499.89 124.74 500 ;
      LAYER M3 ;
        RECT 124.63 499.89 124.74 500 ;
      LAYER M2 ;
        RECT 124.63 499.89 124.74 500 ;
      LAYER M1 ;
        RECT 124.63 499.89 124.74 500 ;
    END
  END READEN
  PIN RSTB
    DIRECTION INPUT ;
    USE SIGNAL ;
    ANTENNAPARTIALMETALAREA 0.20435 LAYER M3 ;
    ANTENNAPARTIALMETALAREA 0.0143 LAYER M2 ;
    ANTENNAPARTIALMETALAREA 0.0143 LAYER M4 ;
    ANTENNAPARTIALMETALAREA 0.0143 LAYER M1 ;
    ANTENNAPARTIALCUTAREA 0.005 LAYER VIA3 ;
    ANTENNAPARTIALCUTAREA 0.005 LAYER VIA2 ;
    ANTENNAPARTIALCUTAREA 0.005 LAYER VIA1 ;
    ANTENNAMODEL OXIDE1 ;
      ANTENNAGATEAREA 0.0434 LAYER M3 ;
      ANTENNAGATEAREA 0.0434 LAYER M4 ;
      ANTENNAMAXAREACAR 5.514977 LAYER M3 ;
      ANTENNAMAXAREACAR 6.123272 LAYER M4 ;
      ANTENNAMAXSIDEAREACAR 10.5553 LAYER M3 ;
      ANTENNAMAXSIDEAREACAR 12.006912 LAYER M4 ;
      ANTENNAMAXCUTCAR 0.345622 LAYER VIA3 ;
    PORT
      LAYER M4 ;
        RECT 159.16 499.89 159.27 500 ;
      LAYER M3 ;
        RECT 159.16 499.89 159.27 500 ;
      LAYER M2 ;
        RECT 159.16 499.89 159.27 500 ;
      LAYER M1 ;
        RECT 159.16 499.89 159.27 500 ;
    END
  END RSTB
  PIN SELTM
    DIRECTION INPUT ;
    USE SIGNAL ;
    ANTENNAPARTIALMETALAREA 0.21865 LAYER M3 ;
    ANTENNAPARTIALMETALAREA 0.0143 LAYER M2 ;
    ANTENNAPARTIALMETALAREA 0.0143 LAYER M4 ;
    ANTENNAPARTIALMETALAREA 0.0143 LAYER M1 ;
    ANTENNAPARTIALCUTAREA 0.005 LAYER VIA3 ;
    ANTENNAPARTIALCUTAREA 0.005 LAYER VIA2 ;
    ANTENNAPARTIALCUTAREA 0.005 LAYER VIA1 ;
    ANTENNAMODEL OXIDE1 ;
      ANTENNAGATEAREA 0.0217 LAYER M3 ;
      ANTENNAGATEAREA 0.0217 LAYER M4 ;
      ANTENNAMAXAREACAR 12.52765 LAYER M3 ;
      ANTENNAMAXAREACAR 13.74424 LAYER M4 ;
      ANTENNAMAXSIDEAREACAR 24.345622 LAYER M3 ;
      ANTENNAMAXSIDEAREACAR 27.248848 LAYER M4 ;
      ANTENNAMAXCUTCAR 0.691244 LAYER VIA3 ;
    PORT
      LAYER M4 ;
        RECT 126.25 499.89 126.36 500 ;
      LAYER M3 ;
        RECT 126.25 499.89 126.36 500 ;
      LAYER M2 ;
        RECT 126.25 499.89 126.36 500 ;
      LAYER M1 ;
        RECT 126.25 499.89 126.36 500 ;
    END
  END SELTM
  PIN WEB
    DIRECTION INPUT ;
    USE SIGNAL ;
    ANTENNAPARTIALMETALAREA 0.20435 LAYER M3 ;
    ANTENNAPARTIALMETALAREA 0.0143 LAYER M2 ;
    ANTENNAPARTIALMETALAREA 0.0143 LAYER M4 ;
    ANTENNAPARTIALMETALAREA 0.0143 LAYER M1 ;
    ANTENNAPARTIALCUTAREA 0.005 LAYER VIA3 ;
    ANTENNAPARTIALCUTAREA 0.005 LAYER VIA2 ;
    ANTENNAPARTIALCUTAREA 0.005 LAYER VIA1 ;
    ANTENNAMODEL OXIDE1 ;
      ANTENNAGATEAREA 0.0434 LAYER M3 ;
      ANTENNAGATEAREA 0.0434 LAYER M4 ;
      ANTENNAMAXAREACAR 5.514977 LAYER M3 ;
      ANTENNAMAXAREACAR 6.123272 LAYER M4 ;
      ANTENNAMAXSIDEAREACAR 10.5553 LAYER M3 ;
      ANTENNAMAXSIDEAREACAR 12.006912 LAYER M4 ;
      ANTENNAMAXCUTCAR 0.345622 LAYER VIA3 ;
    PORT
      LAYER M4 ;
        RECT 157.54 499.89 157.65 500 ;
      LAYER M3 ;
        RECT 157.54 499.89 157.65 500 ;
      LAYER M2 ;
        RECT 157.54 499.89 157.65 500 ;
      LAYER M1 ;
        RECT 157.54 499.89 157.65 500 ;
    END
  END WEB
  PIN GND
    DIRECTION INOUT ;
    USE GROUND ;
    SHAPE RING ;
    PORT
      LAYER M5 ;
        RECT 455 0 459 500 ;
        RECT 450.5 0 454.5 500 ;
        RECT 5.5 0 9.5 500 ;
        RECT 1 0 5 500 ;
      LAYER M4 ;
        RECT 160.21 1 460 5 ;
        RECT 160.21 5.5 460 9.5 ;
        RECT 0 490.5 460 494.5 ;
        RECT 0 495 460 499 ;
        RECT 0 1 109.955 5 ;
        RECT 0 5.5 109.955 9.5 ;
    END
  END GND
  PIN VDD
    DIRECTION INOUT ;
    USE POWER ;
    SHAPE RING ;
    PORT
      LAYER M5 ;
        RECT 446 0 450 500 ;
        RECT 441.5 0 445.5 500 ;
        RECT 14.5 0 18.5 500 ;
        RECT 10 0 14 500 ;
      LAYER M4 ;
        RECT 160.21 10 460 14 ;
        RECT 160.21 14.5 460 18.5 ;
        RECT 0 481.5 460 485.5 ;
        RECT 0 486 460 490 ;
        RECT 0 10 109.955 14 ;
        RECT 0 14.5 109.955 18.5 ;
    END
  END VDD
  PIN VDDIO
    DIRECTION INOUT ;
    USE POWER ;
    SHAPE RING ;
    PORT
      LAYER M5 ;
        RECT 437 0 441 500 ;
        RECT 432.5 0 436.5 500 ;
        RECT 23.5 0 27.5 500 ;
        RECT 19 0 23 500 ;
      LAYER M4 ;
        RECT 160.21 19 460 23 ;
        RECT 160.21 23.5 460 27.5 ;
        RECT 0 472.5 460 476.5 ;
        RECT 0 477 460 481 ;
        RECT 0 19 109.955 23 ;
        RECT 0 23.5 109.955 27.5 ;
    END
  END VDDIO
  OBS
    LAYER M1 SPACING 0.05 ;
      RECT 181.93 0 460 500 ;
      RECT 180.32 0 181.61 500 ;
      RECT 178.71 0 180 500 ;
      RECT 177.1 0 178.39 500 ;
      RECT 175.49 0 176.78 500 ;
      RECT 173.88 0 175.17 500 ;
      RECT 172.27 0 173.56 500 ;
      RECT 170.66 0 171.95 500 ;
      RECT 162.18 0 170.34 500 ;
      RECT 159.375 0 161.86 500 ;
      RECT 157.755 0 159.055 500 ;
      RECT 155.54 0 157.435 500 ;
      RECT 154.005 0 155.22 500 ;
      RECT 152.385 0 153.685 500 ;
      RECT 150.765 0 152.065 500 ;
      RECT 149.145 0 150.445 500 ;
      RECT 147.525 0 148.825 500 ;
      RECT 145.905 0 147.205 500 ;
      RECT 144.285 0 145.585 500 ;
      RECT 142.665 0 143.965 500 ;
      RECT 141.045 0 142.345 500 ;
      RECT 139.425 0 140.725 500 ;
      RECT 137.805 0 139.105 500 ;
      RECT 136.185 0 137.485 500 ;
      RECT 134.565 0 135.865 500 ;
      RECT 132.945 0 134.245 500 ;
      RECT 131.325 0 132.625 500 ;
      RECT 129.705 0 131.005 500 ;
      RECT 128.085 0 129.385 500 ;
      RECT 126.465 0 127.765 500 ;
      RECT 124.845 0 126.145 500 ;
      RECT 123.56 0 124.525 500 ;
      RECT 120.12 0 123.24 500 ;
      RECT 116.88 0 119.8 500 ;
      RECT 115.53 0 116.56 500 ;
      RECT 114.18 0 115.21 500 ;
      RECT 0 0 113.86 500 ;
      RECT 0 0 460 499.785 ;
    LAYER M2 ;
      RECT 181.955 499.285 182.305 499.355 ;
      RECT 181.505 499.285 181.855 499.355 ;
      RECT 181.055 499.285 181.405 499.355 ;
      RECT 180.605 499.285 180.955 499.355 ;
      RECT 180.45 499.035 180.52 499.385 ;
      RECT 178.91 499.035 178.98 499.385 ;
      RECT 178.77 499.035 178.84 499.385 ;
      RECT 178.495 498.23 178.605 499.39 ;
      RECT 176.885 498.45 176.995 499.39 ;
      RECT 176 499.285 176.35 499.355 ;
      RECT 175.55 499.285 175.9 499.355 ;
      RECT 175.275 498.78 175.385 499.39 ;
    LAYER M2 SPACING 0.05 ;
      RECT 181.93 0 460 500 ;
      RECT 180.32 0 181.61 500 ;
      RECT 178.71 0 180 500 ;
      RECT 177.1 0 178.39 500 ;
      RECT 175.49 0 176.78 500 ;
      RECT 173.88 0 175.17 500 ;
      RECT 172.27 0 173.56 500 ;
      RECT 170.66 0 171.95 500 ;
      RECT 162.18 0 170.34 500 ;
      RECT 159.375 0 161.86 500 ;
      RECT 157.755 0 159.055 500 ;
      RECT 155.54 0 157.435 500 ;
      RECT 154.005 0 155.22 500 ;
      RECT 152.385 0 153.685 500 ;
      RECT 150.765 0 152.065 500 ;
      RECT 149.145 0 150.445 500 ;
      RECT 147.525 0 148.825 500 ;
      RECT 145.905 0 147.205 500 ;
      RECT 144.285 0 145.585 500 ;
      RECT 142.665 0 143.965 500 ;
      RECT 141.045 0 142.345 500 ;
      RECT 139.425 0 140.725 500 ;
      RECT 137.805 0 139.105 500 ;
      RECT 136.185 0 137.485 500 ;
      RECT 134.565 0 135.865 500 ;
      RECT 132.945 0 134.245 500 ;
      RECT 131.325 0 132.625 500 ;
      RECT 129.705 0 131.005 500 ;
      RECT 128.085 0 129.385 500 ;
      RECT 126.465 0 127.765 500 ;
      RECT 124.845 0 126.145 500 ;
      RECT 123.56 0 124.525 500 ;
      RECT 120.12 0 123.24 500 ;
      RECT 116.88 0 119.8 500 ;
      RECT 115.53 0 116.56 500 ;
      RECT 114.18 0 115.21 500 ;
      RECT 0 0 113.86 500 ;
      RECT 0 0 460 499.785 ;
    LAYER M3 ;
      RECT 173.665 498.89 173.775 499.39 ;
      RECT 173.465 498.89 173.775 499 ;
      RECT 173.465 416.09 173.575 499 ;
      RECT 123.345 495.885 123.455 499.39 ;
      RECT 123.345 495.885 123.805 495.995 ;
      RECT 123.695 416.5 123.805 495.995 ;
      RECT 181.715 497.79 181.825 499.39 ;
      RECT 180.105 498.01 180.215 499.39 ;
      RECT 173.94 499.265 174.29 499.335 ;
      RECT 173.115 499.015 173.185 499.365 ;
      RECT 172.695 499.015 172.765 499.365 ;
      RECT 172.555 499.015 172.625 499.365 ;
      RECT 172.415 499.015 172.485 499.365 ;
      RECT 172.055 498.725 172.165 499.39 ;
      RECT 171.715 499.015 171.785 499.365 ;
      RECT 171.575 499.015 171.645 499.365 ;
      RECT 170.875 499.015 170.945 499.365 ;
      RECT 170.735 499.015 170.805 499.365 ;
      RECT 170.445 498.505 170.555 499.39 ;
      RECT 170.175 499.015 170.245 499.365 ;
      RECT 170.035 499.015 170.105 499.365 ;
      RECT 161.965 497.985 162.075 499.39 ;
      RECT 159.16 498.115 159.27 499.39 ;
      RECT 157.54 498.115 157.65 499.39 ;
      RECT 155.325 498.16 155.435 499.39 ;
      RECT 153.79 497.985 153.9 499.39 ;
      RECT 153.21 499.295 153.56 499.365 ;
      RECT 152.17 497.985 152.28 499.39 ;
      RECT 150.55 497.985 150.66 499.39 ;
      RECT 148.93 497.985 149.04 499.39 ;
      RECT 147.31 497.985 147.42 499.39 ;
      RECT 145.69 497.985 145.8 499.39 ;
      RECT 144.07 497.985 144.18 499.39 ;
      RECT 142.45 497.985 142.56 499.39 ;
      RECT 140.83 497.985 140.94 499.39 ;
      RECT 139.21 497.985 139.32 499.39 ;
      RECT 137.59 497.985 137.7 499.39 ;
      RECT 135.97 497.985 136.08 499.39 ;
      RECT 135.44 499.31 135.79 499.38 ;
      RECT 134.35 497.985 134.46 499.39 ;
      RECT 132.73 497.985 132.84 499.39 ;
      RECT 131.11 497.985 131.22 499.39 ;
      RECT 129.49 497.985 129.6 499.39 ;
      RECT 127.87 497.985 127.98 499.39 ;
      RECT 126.25 497.985 126.36 499.39 ;
      RECT 124.63 497.985 124.74 499.39 ;
      RECT 124.07 499.285 124.42 499.355 ;
      RECT 123.62 499.285 123.97 499.355 ;
      RECT 119.905 497.985 120.015 499.39 ;
      RECT 116.665 497.985 116.775 499.39 ;
      RECT 115.315 497.985 115.425 499.39 ;
      RECT 113.965 497.985 114.075 499.39 ;
    LAYER M3 SPACING 0.05 ;
      RECT 181.93 0 460 500 ;
      RECT 180.32 0 181.61 500 ;
      RECT 178.71 0 180 500 ;
      RECT 177.1 0 178.39 500 ;
      RECT 175.49 0 176.78 500 ;
      RECT 173.88 0 175.17 500 ;
      RECT 172.27 0 173.56 500 ;
      RECT 170.66 0 171.95 500 ;
      RECT 162.18 0 170.34 500 ;
      RECT 159.375 0 161.86 500 ;
      RECT 157.755 0 159.055 500 ;
      RECT 155.54 0 157.435 500 ;
      RECT 154.005 0 155.22 500 ;
      RECT 152.385 0 153.685 500 ;
      RECT 150.765 0 152.065 500 ;
      RECT 149.145 0 150.445 500 ;
      RECT 147.525 0 148.825 500 ;
      RECT 145.905 0 147.205 500 ;
      RECT 144.285 0 145.585 500 ;
      RECT 142.665 0 143.965 500 ;
      RECT 141.045 0 142.345 500 ;
      RECT 139.425 0 140.725 500 ;
      RECT 137.805 0 139.105 500 ;
      RECT 136.185 0 137.485 500 ;
      RECT 134.565 0 135.865 500 ;
      RECT 132.945 0 134.245 500 ;
      RECT 131.325 0 132.625 500 ;
      RECT 129.705 0 131.005 500 ;
      RECT 128.085 0 129.385 500 ;
      RECT 126.465 0 127.765 500 ;
      RECT 124.845 0 126.145 500 ;
      RECT 123.56 0 124.525 500 ;
      RECT 120.12 0 123.24 500 ;
      RECT 116.88 0 119.8 500 ;
      RECT 115.53 0 116.56 500 ;
      RECT 114.18 0 115.21 500 ;
      RECT 0 0 113.86 500 ;
      RECT 0 0 460 499.785 ;
    LAYER M4 ;
      RECT 152.56 28 460 32 ;
      RECT 289.715 32.5 460 36.5 ;
      RECT 289.715 463.5 460 467.5 ;
      RECT 1 468 460 472 ;
      RECT 152.56 1 159.71 5 ;
      RECT 152.56 5.5 159.71 9.5 ;
      RECT 152.56 10 159.71 14 ;
      RECT 152.56 14.5 159.71 18.5 ;
      RECT 152.56 19 159.71 23 ;
      RECT 152.56 23.5 159.71 27.5 ;
      RECT 110.46 4.115 110.81 4.185 ;
      RECT 110.46 4.255 110.81 4.325 ;
      RECT 110.46 4.395 110.81 4.465 ;
      RECT 110.46 4.535 110.81 4.605 ;
      RECT 110.46 4.675 110.81 4.745 ;
      RECT 110.46 12.09 110.81 12.16 ;
      RECT 110.46 12.23 110.81 12.3 ;
      RECT 110.46 12.37 110.81 12.44 ;
      RECT 110.46 12.51 110.81 12.58 ;
      RECT 110.46 12.65 110.81 12.72 ;
      RECT 110.46 12.79 110.81 12.86 ;
      RECT 110.46 20.17 110.81 20.24 ;
      RECT 110.46 20.31 110.81 20.38 ;
      RECT 110.46 20.45 110.81 20.52 ;
      RECT 110.46 20.59 110.81 20.66 ;
      RECT 110.46 20.73 110.81 20.8 ;
      RECT 110.46 20.87 110.81 20.94 ;
      RECT 110.46 25.175 110.81 25.245 ;
      RECT 110.46 3.555 110.53 3.905 ;
      RECT 110.46 6.635 110.53 6.985 ;
      RECT 110.46 7.085 110.53 7.435 ;
      RECT 110.46 7.535 110.53 7.885 ;
      RECT 110.46 7.985 110.53 8.335 ;
      RECT 110.46 10.13 110.53 10.48 ;
      RECT 110.46 10.58 110.53 10.93 ;
      RECT 110.46 11.03 110.53 11.38 ;
      RECT 110.46 11.48 110.53 11.83 ;
      RECT 110.46 14.715 110.53 15.065 ;
      RECT 110.46 15.165 110.53 15.515 ;
      RECT 110.46 15.615 110.53 15.965 ;
      RECT 110.46 16.065 110.53 16.415 ;
      RECT 110.46 18.21 110.53 18.56 ;
      RECT 110.46 18.66 110.53 19.01 ;
      RECT 110.46 19.11 110.53 19.46 ;
      RECT 110.46 19.56 110.53 19.91 ;
      RECT 110.46 22.795 110.53 23.145 ;
      RECT 110.46 23.245 110.53 23.595 ;
      RECT 110.46 23.695 110.53 24.045 ;
      RECT 110.46 24.145 110.53 24.495 ;
      RECT 110.46 24.595 110.53 24.945 ;
      RECT 110.46 27.1 110.53 27.45 ;
      RECT 110.46 27.55 110.53 27.9 ;
      RECT 110.46 28 110.53 28.35 ;
      RECT 1 28 109.955 32 ;
    LAYER M4 SPACING 0.05 ;
      RECT 0 27.605 460 472.395 ;
      RECT 110.06 0 160.105 472.395 ;
      RECT 0 23.105 460 23.395 ;
      RECT 0 18.605 460 18.895 ;
      RECT 0 14.105 460 14.395 ;
      RECT 0 9.605 460 9.895 ;
      RECT 0 5.105 460 5.395 ;
      RECT 0 0 460 0.895 ;
      RECT 181.93 499.105 460 500 ;
      RECT 180.32 499.105 181.61 500 ;
      RECT 178.71 499.105 180 500 ;
      RECT 177.1 499.105 178.39 500 ;
      RECT 175.49 499.105 176.78 500 ;
      RECT 173.88 499.105 175.17 500 ;
      RECT 172.27 499.105 173.56 500 ;
      RECT 170.66 499.105 171.95 500 ;
      RECT 162.18 499.105 170.34 500 ;
      RECT 159.375 499.105 161.86 500 ;
      RECT 157.755 499.105 159.055 500 ;
      RECT 155.54 499.105 157.435 500 ;
      RECT 154.005 499.105 155.22 500 ;
      RECT 152.385 499.105 153.685 500 ;
      RECT 150.765 499.105 152.065 500 ;
      RECT 149.145 499.105 150.445 500 ;
      RECT 147.525 499.105 148.825 500 ;
      RECT 145.905 499.105 147.205 500 ;
      RECT 144.285 499.105 145.585 500 ;
      RECT 142.665 499.105 143.965 500 ;
      RECT 141.045 499.105 142.345 500 ;
      RECT 139.425 499.105 140.725 500 ;
      RECT 137.805 499.105 139.105 500 ;
      RECT 136.185 499.105 137.485 500 ;
      RECT 134.565 499.105 135.865 500 ;
      RECT 132.945 499.105 134.245 500 ;
      RECT 131.325 499.105 132.625 500 ;
      RECT 129.705 499.105 131.005 500 ;
      RECT 128.085 499.105 129.385 500 ;
      RECT 126.465 499.105 127.765 500 ;
      RECT 124.845 499.105 126.145 500 ;
      RECT 123.56 499.105 124.525 500 ;
      RECT 120.12 499.105 123.24 500 ;
      RECT 116.88 499.105 119.8 500 ;
      RECT 115.53 499.105 116.56 500 ;
      RECT 114.18 499.105 115.21 500 ;
      RECT 0 499.105 113.86 500 ;
      RECT 0 499.105 460 499.785 ;
      RECT 0 476.605 460 476.895 ;
      RECT 0 481.105 460 481.395 ;
      RECT 0 485.605 460 485.895 ;
      RECT 0 490.105 460 490.395 ;
      RECT 0 494.605 460 494.895 ;
    LAYER M5 ;
      RECT 428 1 432 499 ;
      RECT 423.5 1 427.5 499 ;
      RECT 395.095 1 399.095 499 ;
      RECT 382.21 1 386.21 499 ;
      RECT 342.1 1 346.1 499 ;
      RECT 304.115 1 308.115 499 ;
      RECT 299.315 1 303.315 499 ;
      RECT 294.515 1 298.515 499 ;
      RECT 289.715 1 293.715 499 ;
      RECT 252.97 1 256.97 66.965 ;
      RECT 199.6 406.21 203.6 499 ;
      RECT 183.325 380.4 183.565 499 ;
      RECT 174.61 1 178.61 499 ;
      RECT 169.81 1 173.81 499 ;
      RECT 165.01 1 169.01 499 ;
      RECT 160.21 1 164.21 499 ;
      RECT 105.555 1 156.96 5 ;
      RECT 105.555 5.5 156.96 9.5 ;
      RECT 32.5 1 36.5 499 ;
      RECT 28 1 32 499 ;
    LAYER M5 SPACING 0.05 ;
      RECT 428 1 432 499 ;
      RECT 423.5 1 427.5 499 ;
      RECT 395.095 1 399.095 499 ;
      RECT 382.21 1 386.21 499 ;
      RECT 342.1 1 346.1 499 ;
      RECT 304.115 1 308.115 499 ;
      RECT 299.315 1 303.315 499 ;
      RECT 294.515 1 298.515 499 ;
      RECT 289.715 1 293.715 499 ;
      RECT 199.6 27.605 203.6 499 ;
      RECT 183.325 27.605 183.565 499 ;
      RECT 174.61 1 178.61 499 ;
      RECT 169.81 1 173.81 499 ;
      RECT 165.01 1 169.01 499 ;
      RECT 160.21 1 164.21 499 ;
      RECT 32.5 1 36.5 499 ;
      RECT 28 1 32 499 ;
      RECT 27.605 494.605 432.395 494.895 ;
      RECT 27.605 490.105 432.395 490.395 ;
      RECT 27.605 485.605 432.395 485.895 ;
      RECT 27.605 481.105 432.395 481.395 ;
      RECT 411.575 19 415.575 481 ;
      RECT 358.17 19 362.17 481 ;
      RECT 329.42 19 333.42 481 ;
      RECT 322.765 19 326.765 481 ;
      RECT 27.605 476.605 432.395 476.895 ;
      RECT 27.605 27.605 432.395 472.395 ;
      RECT 252.97 1 256.97 472.395 ;
      RECT 110.06 5.105 164.21 472.395 ;
      RECT 105.555 23.5 164.21 27.5 ;
      RECT 27.605 23.105 432.395 23.395 ;
      RECT 105.555 19 164.21 23 ;
      RECT 27.605 18.605 432.395 18.895 ;
      RECT 105.555 14.5 164.21 18.5 ;
      RECT 27.605 14.105 432.395 14.395 ;
      RECT 105.555 10 164.21 14 ;
      RECT 27.605 9.605 432.395 9.895 ;
      RECT 105.555 5.5 164.21 9.5 ;
      RECT 27.605 5.105 432.395 5.395 ;
      RECT 110.06 0 160.105 472.395 ;
      RECT 105.555 1 160.105 5 ;
      RECT 27.605 0 432.395 0.895 ;
      RECT 181.93 499.105 432.395 500 ;
      RECT 180.32 499.105 181.61 500 ;
      RECT 178.71 499.105 180 500 ;
      RECT 177.1 499.105 178.39 500 ;
      RECT 175.49 499.105 176.78 500 ;
      RECT 173.88 499.105 175.17 500 ;
      RECT 172.27 499.105 173.56 500 ;
      RECT 170.66 499.105 171.95 500 ;
      RECT 162.18 499.105 170.34 500 ;
      RECT 159.375 499.105 161.86 500 ;
      RECT 157.755 499.105 159.055 500 ;
      RECT 155.54 499.105 157.435 500 ;
      RECT 154.005 499.105 155.22 500 ;
      RECT 152.385 499.105 153.685 500 ;
      RECT 150.765 499.105 152.065 500 ;
      RECT 149.145 499.105 150.445 500 ;
      RECT 147.525 499.105 148.825 500 ;
      RECT 145.905 499.105 147.205 500 ;
      RECT 144.285 499.105 145.585 500 ;
      RECT 142.665 499.105 143.965 500 ;
      RECT 141.045 499.105 142.345 500 ;
      RECT 139.425 499.105 140.725 500 ;
      RECT 137.805 499.105 139.105 500 ;
      RECT 136.185 499.105 137.485 500 ;
      RECT 134.565 499.105 135.865 500 ;
      RECT 132.945 499.105 134.245 500 ;
      RECT 131.325 499.105 132.625 500 ;
      RECT 129.705 499.105 131.005 500 ;
      RECT 128.085 499.105 129.385 500 ;
      RECT 126.465 499.105 127.765 500 ;
      RECT 124.845 499.105 126.145 500 ;
      RECT 123.56 499.105 124.525 500 ;
      RECT 120.12 499.105 123.24 500 ;
      RECT 116.88 499.105 119.8 500 ;
      RECT 115.53 499.105 116.56 500 ;
      RECT 114.18 499.105 115.21 500 ;
      RECT 27.605 499.105 113.86 500 ;
      RECT 27.605 499.105 432.395 499.785 ;
      RECT 459.105 0 460 0.895 ;
      RECT 459.105 5.105 460 5.395 ;
      RECT 459.105 9.605 460 9.895 ;
      RECT 459.105 14.105 460 14.395 ;
      RECT 459.105 18.605 460 18.895 ;
      RECT 459.105 23.105 460 23.395 ;
      RECT 459.105 27.605 460 472.395 ;
      RECT 459.105 476.605 460 476.895 ;
      RECT 459.105 481.105 460 481.395 ;
      RECT 459.105 485.605 460 485.895 ;
      RECT 459.105 490.105 460 490.395 ;
      RECT 459.105 494.605 460 494.895 ;
      RECT 459.105 499.105 460 500 ;
      RECT 454.605 0 454.895 0.895 ;
      RECT 454.605 5.105 454.895 5.395 ;
      RECT 454.605 9.605 454.895 9.895 ;
      RECT 454.605 14.105 454.895 14.395 ;
      RECT 454.605 18.605 454.895 18.895 ;
      RECT 454.605 23.105 454.895 23.395 ;
      RECT 454.605 27.605 454.895 472.395 ;
      RECT 454.605 476.605 454.895 476.895 ;
      RECT 454.605 481.105 454.895 481.395 ;
      RECT 454.605 485.605 454.895 485.895 ;
      RECT 454.605 490.105 454.895 490.395 ;
      RECT 454.605 494.605 454.895 494.895 ;
      RECT 454.605 499.105 454.895 500 ;
      RECT 450.105 0 450.395 0.895 ;
      RECT 450.105 5.105 450.395 5.395 ;
      RECT 450.105 9.605 450.395 9.895 ;
      RECT 450.105 14.105 450.395 14.395 ;
      RECT 450.105 18.605 450.395 18.895 ;
      RECT 450.105 23.105 450.395 23.395 ;
      RECT 450.105 27.605 450.395 472.395 ;
      RECT 450.105 476.605 450.395 476.895 ;
      RECT 450.105 481.105 450.395 481.395 ;
      RECT 450.105 485.605 450.395 485.895 ;
      RECT 450.105 490.105 450.395 490.395 ;
      RECT 450.105 494.605 450.395 494.895 ;
      RECT 450.105 499.105 450.395 500 ;
      RECT 445.605 0 445.895 0.895 ;
      RECT 445.605 5.105 445.895 5.395 ;
      RECT 445.605 9.605 445.895 9.895 ;
      RECT 445.605 14.105 445.895 14.395 ;
      RECT 445.605 18.605 445.895 18.895 ;
      RECT 445.605 23.105 445.895 23.395 ;
      RECT 445.605 27.605 445.895 472.395 ;
      RECT 445.605 476.605 445.895 476.895 ;
      RECT 445.605 481.105 445.895 481.395 ;
      RECT 445.605 485.605 445.895 485.895 ;
      RECT 445.605 490.105 445.895 490.395 ;
      RECT 445.605 494.605 445.895 494.895 ;
      RECT 445.605 499.105 445.895 500 ;
      RECT 441.105 0 441.395 0.895 ;
      RECT 441.105 5.105 441.395 5.395 ;
      RECT 441.105 9.605 441.395 9.895 ;
      RECT 441.105 14.105 441.395 14.395 ;
      RECT 441.105 18.605 441.395 18.895 ;
      RECT 441.105 23.105 441.395 23.395 ;
      RECT 441.105 27.605 441.395 472.395 ;
      RECT 441.105 476.605 441.395 476.895 ;
      RECT 441.105 481.105 441.395 481.395 ;
      RECT 441.105 485.605 441.395 485.895 ;
      RECT 441.105 490.105 441.395 490.395 ;
      RECT 441.105 494.605 441.395 494.895 ;
      RECT 441.105 499.105 441.395 500 ;
      RECT 436.605 0 436.895 0.895 ;
      RECT 436.605 5.105 436.895 5.395 ;
      RECT 436.605 9.605 436.895 9.895 ;
      RECT 436.605 14.105 436.895 14.395 ;
      RECT 436.605 18.605 436.895 18.895 ;
      RECT 436.605 23.105 436.895 23.395 ;
      RECT 436.605 27.605 436.895 472.395 ;
      RECT 436.605 476.605 436.895 476.895 ;
      RECT 436.605 481.105 436.895 481.395 ;
      RECT 436.605 485.605 436.895 485.895 ;
      RECT 436.605 490.105 436.895 490.395 ;
      RECT 436.605 494.605 436.895 494.895 ;
      RECT 436.605 499.105 436.895 500 ;
      RECT 23.105 0 23.395 0.895 ;
      RECT 23.105 5.105 23.395 5.395 ;
      RECT 23.105 9.605 23.395 9.895 ;
      RECT 23.105 14.105 23.395 14.395 ;
      RECT 23.105 18.605 23.395 18.895 ;
      RECT 23.105 23.105 23.395 23.395 ;
      RECT 23.105 27.605 23.395 472.395 ;
      RECT 23.105 476.605 23.395 476.895 ;
      RECT 23.105 481.105 23.395 481.395 ;
      RECT 23.105 485.605 23.395 485.895 ;
      RECT 23.105 490.105 23.395 490.395 ;
      RECT 23.105 494.605 23.395 494.895 ;
      RECT 23.105 499.105 23.395 500 ;
      RECT 18.605 0 18.895 0.895 ;
      RECT 18.605 5.105 18.895 5.395 ;
      RECT 18.605 9.605 18.895 9.895 ;
      RECT 18.605 14.105 18.895 14.395 ;
      RECT 18.605 18.605 18.895 18.895 ;
      RECT 18.605 23.105 18.895 23.395 ;
      RECT 18.605 27.605 18.895 472.395 ;
      RECT 18.605 476.605 18.895 476.895 ;
      RECT 18.605 481.105 18.895 481.395 ;
      RECT 18.605 485.605 18.895 485.895 ;
      RECT 18.605 490.105 18.895 490.395 ;
      RECT 18.605 494.605 18.895 494.895 ;
      RECT 18.605 499.105 18.895 500 ;
      RECT 14.105 0 14.395 0.895 ;
      RECT 14.105 5.105 14.395 5.395 ;
      RECT 14.105 9.605 14.395 9.895 ;
      RECT 14.105 14.105 14.395 14.395 ;
      RECT 14.105 18.605 14.395 18.895 ;
      RECT 14.105 23.105 14.395 23.395 ;
      RECT 14.105 27.605 14.395 472.395 ;
      RECT 14.105 476.605 14.395 476.895 ;
      RECT 14.105 481.105 14.395 481.395 ;
      RECT 14.105 485.605 14.395 485.895 ;
      RECT 14.105 490.105 14.395 490.395 ;
      RECT 14.105 494.605 14.395 494.895 ;
      RECT 14.105 499.105 14.395 500 ;
      RECT 9.605 0 9.895 0.895 ;
      RECT 9.605 5.105 9.895 5.395 ;
      RECT 9.605 9.605 9.895 9.895 ;
      RECT 9.605 14.105 9.895 14.395 ;
      RECT 9.605 18.605 9.895 18.895 ;
      RECT 9.605 23.105 9.895 23.395 ;
      RECT 9.605 27.605 9.895 472.395 ;
      RECT 9.605 476.605 9.895 476.895 ;
      RECT 9.605 481.105 9.895 481.395 ;
      RECT 9.605 485.605 9.895 485.895 ;
      RECT 9.605 490.105 9.895 490.395 ;
      RECT 9.605 494.605 9.895 494.895 ;
      RECT 9.605 499.105 9.895 500 ;
      RECT 5.105 0 5.395 0.895 ;
      RECT 5.105 5.105 5.395 5.395 ;
      RECT 5.105 9.605 5.395 9.895 ;
      RECT 5.105 14.105 5.395 14.395 ;
      RECT 5.105 18.605 5.395 18.895 ;
      RECT 5.105 23.105 5.395 23.395 ;
      RECT 5.105 27.605 5.395 472.395 ;
      RECT 5.105 476.605 5.395 476.895 ;
      RECT 5.105 481.105 5.395 481.395 ;
      RECT 5.105 485.605 5.395 485.895 ;
      RECT 5.105 490.105 5.395 490.395 ;
      RECT 5.105 494.605 5.395 494.895 ;
      RECT 5.105 499.105 5.395 500 ;
      RECT 0 0 0.895 0.895 ;
      RECT 0 5.105 0.895 5.395 ;
      RECT 0 9.605 0.895 9.895 ;
      RECT 0 14.105 0.895 14.395 ;
      RECT 0 18.605 0.895 18.895 ;
      RECT 0 23.105 0.895 23.395 ;
      RECT 0 27.605 0.895 472.395 ;
      RECT 0 476.605 0.895 476.895 ;
      RECT 0 481.105 0.895 481.395 ;
      RECT 0 485.605 0.895 485.895 ;
      RECT 0 490.105 0.895 490.395 ;
      RECT 0 494.605 0.895 494.895 ;
      RECT 0 499.105 0.895 500 ;
  END
END kpts28hpc128_r08w01_45c5pl_0v0

END LIBRARY
